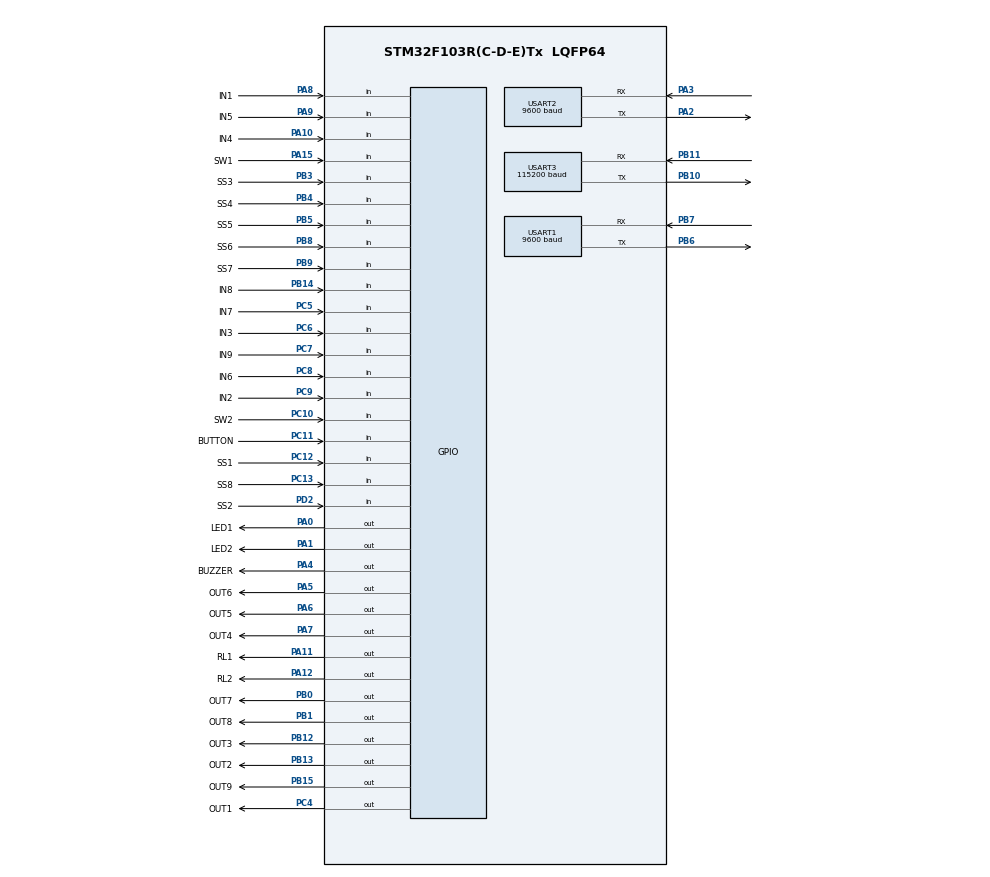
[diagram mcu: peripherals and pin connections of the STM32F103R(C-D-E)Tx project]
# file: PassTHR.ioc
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Mcu.Family=STM32F1
Mcu.Name=STM32F103R(C-D-E)Tx
Mcu.Package=LQFP64
NVIC.PriorityGroup=NVIC_PRIORITYGROUP_4
NVIC.TIM4_IRQn=true\:0\:0\:false\:false\:true\:true\:true
NVIC.TIM5_IRQn=true\:0\:0\:false\:false\:true\:true\:true
NVIC.TIM6_IRQn=true\:0\:0\:false\:false\:true\:true\:true
NVIC.TIM7_IRQn=true\:0\:0\:false\:false\:true\:true\:true
NVIC.USART1_IRQn=true\:0\:0\:false\:false\:true\:true\:true
NVIC.USART2_IRQn=true\:0\:0\:false\:false\:true\:true\:true
NVIC.USART3_IRQn=true\:0\:0\:false\:false\:true\:true\:true
PA0-WKUP.GPIO_Label=LED1
PA0-WKUP.Signal=GPIO_Output
PA1.GPIO_Label=LED2
PA1.Signal=GPIO_Output
PA10.GPIO_Label=IN4
PA10.Signal=GPIO_Input
PA11.GPIO_Label=RL1
PA11.Signal=GPIO_Output
PA12.GPIO_Label=RL2
PA12.Signal=GPIO_Output
PA13.Mode=Serial_Wire
PA13.Signal=SYS_JTMS-SWDIO
PA14.Mode=Serial_Wire
PA14.Signal=SYS_JTCK-SWCLK
PA15.GPIO_Label=SW1
PA15.Signal=GPIO_Input
PA2.Mode=Asynchronous
PA2.Signal=USART2_TX
PA3.Mode=Asynchronous
PA3.Signal=USART2_RX
PA4.GPIO_Label=BUZZER
PA4.Signal=GPIO_Output
PA5.GPIO_Label=OUT6
PA5.Signal=GPIO_Output
PA6.GPIO_Label=OUT5
PA6.Signal=GPIO_Output
PA7.GPIO_Label=OUT4
PA7.Signal=GPIO_Output
PA8.GPIO_Label=IN1
PA8.Signal=GPIO_Input
PA9.GPIO_Label=IN5
PA9.GPIO_PuPd=GPIO_PULLUP
PA9.Signal=GPIO_Input
PB0.GPIO_Label=OUT7
PB0.Signal=GPIO_Output
PB1.GPIO_Label=OUT8
PB1.Signal=GPIO_Output
PB10.Mode=Asynchronous
PB10.Signal=USART3_TX
PB11.Mode=Asynchronous
PB11.Signal=USART3_RX
PB12.GPIO_Label=OUT3
PB12.Signal=GPIO_Output
PB13.GPIO_Label=OUT2
PB13.Signal=GPIO_Output
PB14.GPIO_Label=IN8
PB14.Signal=GPIO_Input
PB15.GPIO_Label=OUT9
PB15.Signal=GPIO_Output
PB3.GPIO_Label=SS3
PB3.Signal=GPIO_Input
PB4.GPIO_Label=SS4
PB4.Signal=GPIO_Input
PB5.GPIO_Label=SS5
PB5.Signal=GPIO_Input
PB6.Mode=Asynchronous
PB6.Signal=USART1_TX
PB7.Mode=Asynchronous
PB7.Signal=USART1_RX
PB8.GPIO_Label=SS6
PB8.Signal=GPIO_Input
PB9.GPIO_Label=SS7
PB9.Signal=GPIO_Input
PC10.GPIO_Label=SW2
PC10.Signal=GPIO_Input
PC11.GPIO_Label=BUTTON
PC11.Signal=GPIO_Input
PC12.GPIO_Label=SS1
PC12.Signal=GPIO_Input
PC13-TAMPER-RTC.GPIO_Label=SS8
PC13-TAMPER-RTC.Signal=GPIO_Input
PC4.GPIO_Label=OUT1
PC4.Signal=GPIO_Output
PC5.GPIO_Label=IN7
PC5.Signal=GPIO_Input
PC6.GPIO_Label=IN3
PC6.Signal=GPIO_Input
PC7.GPIO_Label=IN9
PC7.Signal=GPIO_Input
PC8.GPIO_Label=IN6
PC8.Signal=GPIO_Input
PC9.GPIO_Label=IN2
PC9.Signal=GPIO_Input
PD2.GPIO_Label=SS2
PD2.Signal=GPIO_Input
ProjectManager.HeapSize=0x200
ProjectManager.StackSize=0x400
ProjectManager.TargetToolchain=MDK-ARM V5.27
RCC.APB1Freq_Value=8000000
RCC.APB2Freq_Value=8000000
TIM4.Period=9
TIM4.Prescaler=799
TIM5.Period=1999
TIM5.Prescaler=399
TIM6.Period=49
TIM6.Prescaler=799
TIM7.Period=19999
TIM7.Prescaler=399
USART1.BaudRate=9600
USART1.VirtualMode=VM_ASYNC
USART2.BaudRate=9600
USART2.VirtualMode=VM_ASYNC
USART3.BaudRate=115200
USART3.VirtualMode=VM_ASYNC
VP_TIM4_VS_ClockSourceINT.Mode=Internal
VP_TIM5_VS_ClockSourceINT.Mode=Internal
VP_TIM6_VS_ClockSourceINT.Mode=Enable_Timer
VP_TIM7_VS_ClockSourceINT.Mode=Enable_Timer
board=custom

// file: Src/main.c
/* USER CODE BEGIN Header */
/**
  ******************************************************************************
  * @file           : main.c
  * @brief          : Main program body
  ******************************************************************************
  * @attention
  *
  * <h2><center>&copy; Copyright (c) 2023 STMicroelectronics.
  * All rights reserved.</center></h2>
  *
  * This software component is licensed by ST under BSD 3-Clause license,
  * the "License"; You may not use this file except in compliance with the
  * License. You may obtain a copy of the License at:
  *                        opensource.org/licenses/BSD-3-Clause
  *
  ******************************************************************************
  */
/* USER CODE END Header */

#include "main.h"
#include "tim.h"
#include "usart.h"
#include "gpio.h"

/* USER CODE BEGIN Includes */
#include "hmi.h"
#include "queue.h"
#include "communicate.h"
/* USER CODE END Includes */

/* USER CODE BEGIN PV */
// extern void readAllInput(sensor_t *pSensor, inputBoard_t *pInput);
/* USER CODE END PV */

void SystemClock_Config(void);

/* USER CODE BEGIN 0 */
extern uint8_t rxBufferHMI[MAX_LENGTH];
extern uint8_t rxData;
extern uint8_t rxDataComm;
extern bool isMaster;
inputBoard_t input;
outputBoard_t output;
sensor_t sensor;
inputBoard_t inputSlave;
outputBoard_t outputSlave;
sensor_t sensorSlave;

collectData_t slaveData = {0};
collectData_t preSlaveData = {0};

bool rxInputManual[IN_MAX*2]={0};
bool rxOutputManual[OUT_MAX*2]={0};
bool rxRelayManual[RELAY_MAX*2]={0};
tickTimer gFlagTimer;
QUEUE sensorQueueHMI, inputQueueHMI, outputQueueHMI, commandQueue;
QUEUE sensorQueueIO, inputQueueIO, outputQueueIO;
MAPPING_DATA_t mappedData;
extern uint8_t rs232Rx[10];
extern bool hmiSetMode;
bool isGPIOTuringOn[21] = {0}; // 0 not turn ON, 1 is turned oN, IN1->9, OUT1->9, RL1->2
uint8_t slaveStatus = SLAVE_NO_CONNECTED;
extern uint32_t timeOutSlave;
bool allowToSendMapData = 0;
#if 0
#if defined(__GNUC__)
int _write(int fd, char * ptr, int len) {
  HAL_UART_Transmit( &huart2, (uint8_t * ) ptr, len, HAL_MAX_DELAY);
  return len;
}
#elif defined(__ICCARM__)
#include "LowLevelIOInterface.h"

size_t __write(int handle,
  const unsigned char * buffer, size_t size) {
  HAL_UART_Transmit( &huart2, (uint8_t * ) buffer, size, HAL_MAX_DELAY);
  return size;
}
#elif defined(__CC_ARM)
int fputc(int ch, FILE * f) {
  HAL_UART_Transmit( &huart2, (uint8_t * ) & ch, 1, HAL_MAX_DELAY);
  return ch;
}
#endif
#endif
/* USER CODE END 0 */

int main(void)
{

  /* MCU Configuration--------------------------------------------------------*/

  /* Reset of all peripherals, Initializes the Flash interface and the Systick. */
  HAL_Init();

  /* Configure the system clock */
  SystemClock_Config();

  /* Initialize all configured peripherals */
  MX_GPIO_Init();
  MX_USART2_UART_Init();
  MX_TIM5_Init();
  MX_TIM6_Init();
  MX_TIM7_Init();
  MX_USART1_UART_Init();
  MX_USART3_UART_Init();
  MX_TIM4_Init();
  /* USER CODE BEGIN 2 */
  memset(&input,  0, sizeof(input));
  memset(&output, 0, sizeof(output));
  memset(&sensor, 0, sizeof(sensor));
  memset(&sensorQueueHMI, 0, sizeof(sensorQueueHMI));
  memset(&sensorQueueIO, 0, sizeof(sensorQueueIO));
  memset(&inputQueueHMI, 0, sizeof(inputQueueHMI));
  memset(&inputQueueIO, 0, sizeof(inputQueueIO));
  memset(&outputQueueHMI, 0, sizeof(outputQueueHMI));
  memset(&outputQueueIO, 0, sizeof(outputQueueIO));
  memset(&mappedData, 0, sizeof(mappedData));

  initializeQueue(&sensorQueueHMI);
  initializeQueue(&sensorQueueIO);
  initializeQueue(&inputQueueHMI);
  initializeQueue(&inputQueueIO);
  initializeQueue(&outputQueueHMI);
  initializeQueue(&outputQueueIO);
  initializeQueue(&commandQueue);

	HAL_UART_Receive_IT(&huart1, &rxData, 1);
	HAL_UART_Receive_IT(&huart2, &rxDataComm, 1);
	HAL_UART_Receive_IT(&huart3, rs232Rx, 10);
	HAL_TIM_Base_Start_IT(&htim4);
  HAL_TIM_Base_Start_IT(&htim5);
  HAL_TIM_Base_Start_IT(&htim6);
  HAL_TIM_Base_Start_IT(&htim7);
  /* USER CODE END 2 */

  /* Infinite loop */
  while (1)
  {

    /* USER CODE BEGIN 3 */

    if(gFlagTimer.Time_1ms)
    {
      turnOffGpioByAutoMode(hmiSetMode, &mappedData);
      gFlagTimer.Time_1ms = 0;
    }
    if(gFlagTimer.Time_5ms)
    {
      readAllInput(&sensor, &input, &output);
        masterSendStatusBoard(sensor, input, output);
      if (memcmp(&preSlaveData, &slaveData, sizeof(collectData_t)))
      {
        memcpy(&sensorSlave, &slaveData, sizeof(sensor_t));
        memcpy(&inputSlave, (&slaveData + sizeof(sensor_t)), sizeof(inputBoard_t));
        memcpy(&outputSlave, (&slaveData + sizeof(sensor_t) + sizeof(inputBoard_t)), sizeof(outputBoard_t));
        memcpy(&preSlaveData, &slaveData, sizeof(collectData_t));
      }
      gFlagTimer.Time_5ms = 0;
    }
    if(gFlagTimer.Time_10ms)
    {
      eventHmiHandler(&commandQueue);
      setGPIOMode(hmiSetMode);
      if (hmiSetMode == AUTO)
      {
        controlGPIOByAutoMode(mappedData);
      }
      else
      {
        controlGPIOByManualMode(hmiSetMode, rxInputManual, rxOutputManual, rxRelayManual);
      }
      gFlagTimer.Time_10ms = 0;
    }
    if(gFlagTimer.Time_50ms)
    {
      changeHmiStatus(hmiSetMode, input, output ,sensor);
      gFlagTimer.Time_50ms = 0;
    }
    if(gFlagTimer.Time_100ms)
    {
      allowToSendMapData = checkSlaveStatus(&slaveStatus, &timeOutSlave);
      gFlagTimer.Time_100ms = 0;
    }
    if(gFlagTimer.Time_1000ms)
    {
			HAL_GPIO_TogglePin(LED1_GPIO_Port,LED1_Pin);
      //if (allowToSendMapData)
      {
        //masterSendMappedData(mappedData);
      }
      gFlagTimer.Time_1000ms = 0;
    }
    if(gFlagTimer.Time_2s)
    {
// #if KEEP_DEBUG
#if 0
      memset(&sensor, 0, sizeof(sensor));
      memset(&input, 0, sizeof(input));
      memset(&output, 0, sizeof(output));
#endif
			HAL_GPIO_TogglePin(LED2_GPIO_Port,LED2_Pin);
      gFlagTimer.Time_2s = 0;
    }

  }
  /* USER CODE END 3 */
}

void SystemClock_Config(void)
{
  RCC_OscInitTypeDef RCC_OscInitStruct = {0};
  RCC_ClkInitTypeDef RCC_ClkInitStruct = {0};

  /** Initializes the CPU, AHB and APB busses clocks
  */
  RCC_OscInitStruct.OscillatorType = RCC_OSCILLATORTYPE_HSI;
  RCC_OscInitStruct.HSIState = RCC_HSI_ON;
  RCC_OscInitStruct.HSICalibrationValue = RCC_HSICALIBRATION_DEFAULT;
  RCC_OscInitStruct.PLL.PLLState = RCC_PLL_ON;
  RCC_OscInitStruct.PLL.PLLSource = RCC_PLLSOURCE_HSI_DIV2;
  RCC_OscInitStruct.PLL.PLLMUL = RCC_PLL_MUL16;
  if (HAL_RCC_OscConfig(&RCC_OscInitStruct) != HAL_OK)
  {
    Error_Handler();
  }
  /** Initializes the CPU, AHB and APB busses clocks
  */
  RCC_ClkInitStruct.ClockType = RCC_CLOCKTYPE_HCLK|RCC_CLOCKTYPE_SYSCLK
                              |RCC_CLOCKTYPE_PCLK1|RCC_CLOCKTYPE_PCLK2;
  RCC_ClkInitStruct.SYSCLKSource = RCC_SYSCLKSOURCE_PLLCLK;
  RCC_ClkInitStruct.AHBCLKDivider = RCC_SYSCLK_DIV1;
  RCC_ClkInitStruct.APB1CLKDivider = RCC_HCLK_DIV2;
  RCC_ClkInitStruct.APB2CLKDivider = RCC_HCLK_DIV1;

  if (HAL_RCC_ClockConfig(&RCC_ClkInitStruct, FLASH_LATENCY_2) != HAL_OK)
  {
    Error_Handler();
  }
}

void Error_Handler(void)
{
}

/************************ (C) COPYRIGHT STMicroelectronics *****END OF FILE****/
